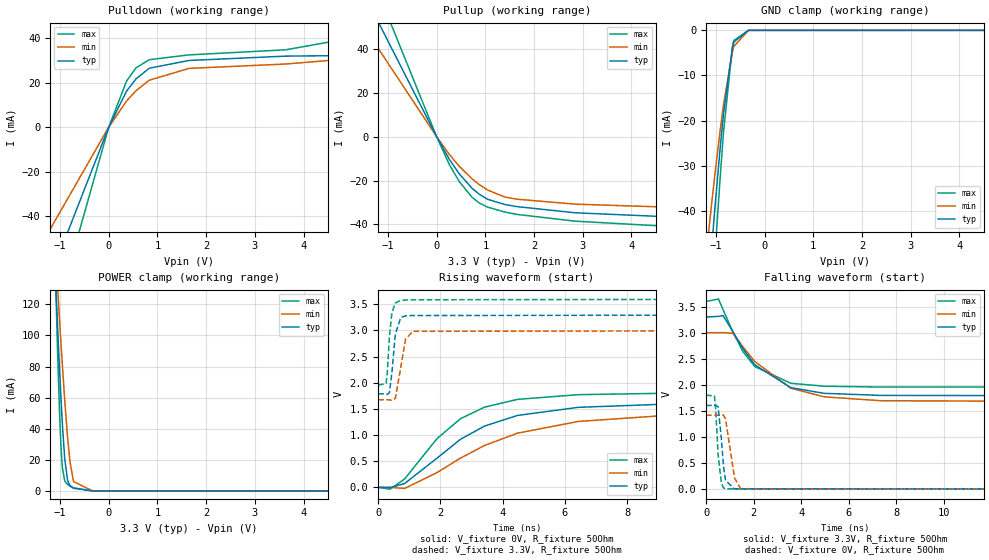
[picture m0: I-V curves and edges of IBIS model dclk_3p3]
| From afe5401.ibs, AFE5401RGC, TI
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|   dclk_3p3 Model
[Model]   dclk_3p3
Model_type   3-state
Polarity   Non-Inverting
Vmeas = 0.9
Vref = 0
Cref = 5pF
Rref = 50
|   typ   min   max
|   (nom PVT)   (fast PVT)   (slow PVT)
C_comp   1.569e-12   1.501e-12   1.667e-12
| Where nom  PVT is Nominal Process, 3.3V, 27C
|   Fast PVT is Strong Process,  3.6V, -40C
|   Slow PVT is Weak Process,   3V, 125C
[Voltage Range]   3.3   3   3.6
|Junction Temperature
[Temperature Range]   27   125   -40
[Pullup Reference]   3.3   3   3.6
[Pulldown Reference]   0   0   0
[Power Clamp Reference]   3.3   3   3.6
[GND Clamp Reference]   0   0   0
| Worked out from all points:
|   slope of the pulldown table from 0 to 0.495 V, typ, clamps not added: 24.7 ohm
|   slope of the pullup table from 0 to 0.495 V, typ, clamps not added: 27.8 ohm
|   POWER clamp passes 1 mA (typ) near -0.65 V on its own axis
|   falling waveform, V_fixture 3.3V, R_fixture 50Ohm: 20-80 % time 1.66ns typ, 2ns min, 1.33ns max; typ from 3.3 V to 1.79 V
|   rising waveform, V_fixture 0V, R_fixture 50Ohm: 20-80 % time 2.46ns typ, 3.24ns min, 1.9ns max; typ from 0 V to 1.61 V
|   rising waveform, V_fixture 3.3V, R_fixture 50Ohm: 20-80 % time 142ps typ, 190ps min, 119ps max; typ from 1.79 V to 3.3 V
|   falling waveform, V_fixture 0V, R_fixture 50Ohm: 20-80 % time 173ps typ, 252ps min, 142ps max; typ from 1.6 V to 0 V
[Pulldown]
|   Voltage   I(typ)   I(min)   I(max)
-3.3V     -185.1mA   -126.1mA   -255.8mA
-3mV      -168.3uA   -114.7uA   -232.5uA
366mV     16.2mA     11.79mA    20.74mA
559.2mV   21.7mA     16.37mA    26.67mA
831mV     26.51mA    21.11mA    30.36mA
1.647V    30.01mA    26.44mA    32.52mA
3.633V    31.97mA    28.41mA    34.81mA
4.498V    32.14mA    29.97mA    38.19mA
5.29V     38.25mA    31.39mA    45.32mA
5.974V    50.12mA    38.95mA    61.62mA
6.29V     58.46mA    44.57mA    72.71mA
6.6V      68.7mA     51.68mA    86.06mA
[GND Clamp]
|   Voltage   I(typ)   I(min)   I(max)
-3.3V     -1.237A    -1.056A    -1.383A
-1.185V   -62.02mA   -48.47mA   -79.23mA
-1.09V    -48.68mA   -38.74mA   -62.09mA
-1.016V   -38.95mA   -31.63mA   -49.47mA
-914.1mV  -26.39mA   -22.38mA   -33mA
-840mV    -18.26mA   -16.29mA   -22.27mA
-660mV    -3.853mA   -4.762mA   -3.675mA
-632.4mV  -2.604mA   -3.574mA   -2.256mA
-330mV    -1.092uA   -13.07uA   -101.3nA
6.6V      0A         0A         0A
[Pullup]
|   Voltage   I(typ)   I(min)   I(max)
-3.3V     144.2mA    111mA      181.3mA
-3mV      131.1uA    100.9uA    164.8uA
260.7mV   -10.34mA   -8.102mA   -12.74mA
462mV     -16.88mA   -13.44mA   -20.42mA
724.8mV   -23.49mA   -19.2mA    -27.59mA
867.9mV   -26.16mA   -21.75mA   -30.15mA
1.046V    -28.58mA   -24.34mA   -32.15mA
1.398V    -30.95mA   -27.54mA   -34.39mA
1.647V    -31.91mA   -28.52mA   -35.47mA
2.835V    -34.73mA   -30.79mA   -38.55mA
5.098V    -36.9mA    -32.42mA   -41.37mA
6.6V      -36.9mA    -32.42mA   -41.37mA
[POWER Clamp]
|   Voltage   I(typ)   I(min)   I(max)
-3.3V     1.983A     1.478A     3.214A
-1.104V   145.1mA    160.1mA    151.1mA
-1.05V    106mA      131.1mA    89.67mA
-1.011V   79.26mA    110.8mA    51.45mA
-981.6mV  60.43mA    95.82mA    29.08mA
-952.8mV  43.58mA    81.6mA     15.12mA
-903mV    20.44mA    58.35mA    6.4mA
-844.8mV  6.804mA    34.5mA     4.15mA
-795mV    3.286mA    18.71mA    3.138mA
-722.7mV  1.758mA    6.011mA    1.936mA
-330mV    1.653uA    10.95uA    250.4nA
6.6V      0A         0A         0A
[Ramp]
R_load = 50
|   typ   min   max
dV/dt_r   0.963548/2.46041e-09   0.850093/3.23116e-09   1.08189/1.89597e-09
dV/dt_f   0.907194/1.66269e-09   0.795985/2.00325e-09   0.987243/1.32794e-09
[Falling Waveform]
V_fixture = 3.3V
V_fixture_min = 3V
V_fixture_max = 3.6V
R_fixture = 50Ohm
|   Time   V(typ)   V(min)   V(max)
0s        3.3V       3V         3.6V
520ps     3.313V     3V         3.645V
715ps     3.328V     3.001V     3.442V
1.13ns    3.017V     2.987V     3.01V
1.55ns    2.694V     2.728V     2.636V
2.05ns    2.383V     2.446V     2.349V
3.565ns   1.945V     1.934V     2.029V
4.975ns   1.836V     1.769V     1.973V
7.34ns    1.797V     1.695V     1.957V
20ns      1.788V     1.673V     1.955V
[Rising Waveform]
V_fixture = 0V
V_fixture_min = 0V
V_fixture_max = 0V
R_fixture = 50Ohm
|   Time   V(typ)   V(min)   V(max)
0s        1.164nV    56.23nV    608.7pV
380ps     -6.246mV   479.9uV    -34.63mV
850ps     73.39mV    -21.18mV   160.8mV
1.89ns    558.7mV    282.7mV    932.3mV
2.645ns   919.5mV    558.6mV    1.313V
3.415ns   1.171V     800.4mV    1.533V
4.475ns   1.375V     1.036V     1.682V
6.43ns    1.53V      1.26V      1.772V
9.02ns    1.586V     1.366V     1.797V
20ns      1.606V     1.417V     1.803V
[Rising Waveform]
V_fixture = 3.3V
V_fixture_min = 3V
V_fixture_max = 3.6V
R_fixture = 50Ohm
|   Time   V(typ)   V(min)   V(max)
0s        1.789V     1.675V     1.955V
255ps     1.786V     1.676V     1.986V
295ps     1.777V     1.675V     2.211V
360ps     1.813V     1.673V     2.882V
440ps     2.188V     1.666V     3.339V
550ps     2.93V      1.701V     3.525V
725ps     3.247V     2.29V      3.575V
880ps     3.279V     2.834V     3.581V
1.115ns   3.285V     2.983V     3.587V
20ns      3.3V       3V         3.6V
[Falling Waveform]
V_fixture = 0V
V_fixture_min = 0V
V_fixture_max = 0V
R_fixture = 50Ohm
|   Time   V(typ)   V(min)   V(max)
0s        1.604V     1.416V     1.801V
350ps     1.605V     1.416V     1.787V
405ps     1.613V     1.416V     1.523V
505ps     1.577V     1.416V     660.2mV
640ps     973.7mV    1.425V     118.4mV
730ps     447.7mV    1.419V     24.88mV
815ps     168.3mV    1.35V      2.83mV
1.195ns   628.2uV    215.1mV    3.469mV
1.46ns    3.623mV    -2.207mV   2.291mV
20ns      -139.1nV   150.8nV    -124.2nV
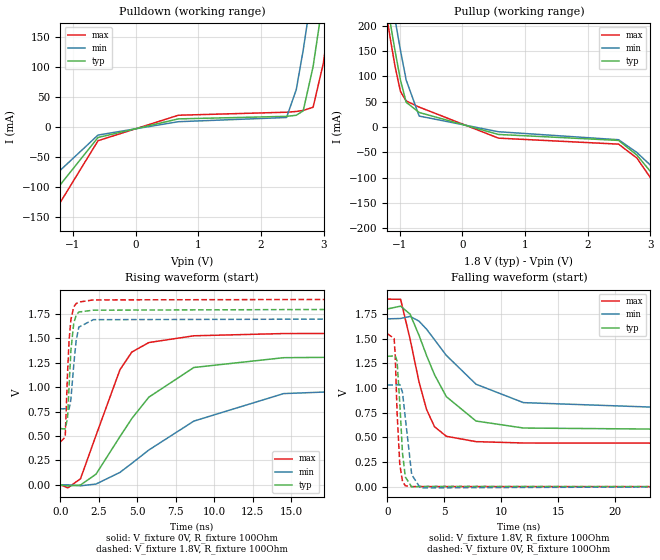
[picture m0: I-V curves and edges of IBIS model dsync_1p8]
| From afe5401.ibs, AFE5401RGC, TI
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|   dsync_1p8 Model
[Model]   dsync_1p8
Model_type   Output
Polarity   Non-Inverting
Vmeas = 0.9
Vref = 0
Cref = 5pF
Rref = 100
|   typ   min   max
|   (nom PVT)   (fast PVT)   (slow PVT)
C_comp   1.711e-12   1.676e-12   1.765e-12
| Where nom  PVT is Nominal Process, 1.8V, 27C
|   Fast PVT is Strong Process,  1.9V, -40C
|   Slow PVT is Weak Process,   1.7V, 125C
[Voltage Range]   1.8   1.7   1.9
|Junction Temperature
[Temperature Range]   27   125   -40
[Pullup Reference]   1.8   1.7   1.9
[Pulldown Reference]   0   0   0
[Power Clamp Reference]   1.8   1.7   1.9
[GND Clamp Reference]   0   0   0
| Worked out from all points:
|   slope of the pulldown table from 0 to 0.27 V, typ, clamps not added: 39.5 ohm
|   slope of the pullup table from 0 to 0.27 V, typ, clamps not added: 31.9 ohm
|   falling waveform, V_fixture 1.8V, R_fixture 100Ohm: 20-80 % time 3.06ns typ, 4.95ns min, 1.79ns max; typ from 1.8 V to 0.577 V
|   rising waveform, V_fixture 0V, R_fixture 100Ohm: 20-80 % time 3.86ns typ, 6.76ns min, 2.16ns max; typ from 0 V to 1.32 V
|   rising waveform, V_fixture 1.8V, R_fixture 100Ohm: 20-80 % time 267ps typ, 325ps min, 246ps max; typ from 0.577 V to 1.8 V
|   falling waveform, V_fixture 0V, R_fixture 100Ohm: 20-80 % time 384ps typ, 543ps min, 312ps max; typ from 1.32 V to 0 V
[Pulldown]
|   Voltage   I(typ)   I(min)   I(max)
-1.8V     -236.1mA   -155mA     -317.1mA
-1.639V   -163.8mA   -117.4mA   -227.2mA
-1.545V   -141.3mA   -105.7mA   -184.4mA
-599.8mV  -17.59mA   -13.54mA   -22.97mA
682mV     13.43mA    8.736mA    19.52mA
2.409V    17.67mA    15.77mA    24.59mA
2.564V    19.46mA    62.19mA    25.8mA
2.675V    26.87mA    128.2mA    27.54mA
2.833V    100.7mA    238.4mA    32.82mA
2.996V    215.2mA    358.9mA    106.1mA
3.201V    372.2mA    516.7mA    258.6mA
3.6V      687mA      828.7mA    575.7mA
[Pullup]
|   Voltage   I(typ)   I(min)   I(max)
-1.8V     721.1mA    774.9mA    698.7mA
-1.186V   231.1mA    293.4mA    200mA
-1.142V   197.9mA    260.3mA    166.6mA
-1.076V   149.8mA    211.9mA    119.3mA
-990.8mV  92.93mA    151.7mA    70.16mA
-899.4mV  48.82mA    92.82mA    51.41mA
-691.6mV  28.54mA    21.5mA     39.21mA
574.2mV   -14.85mA   -9.506mA   -22.14mA
2.491V    -26.62mA   -25.29mA   -33.98mA
2.783V    -55.48mA   -50.45mA   -61.4mA
3.402V    -148.6mA   -122mA     -172.3mA
3.6V      -230.9mA   -188.8mA   -260.5mA
[Ramp]
R_load = 100
|   typ   min   max
dV/dt_r   0.792675/3.84787e-09   0.615366/6.74933e-09   0.930156/2.15375e-09
dV/dt_f   0.7338/3.05246e-09   0.552843/4.92497e-09   0.875843/1.78863e-09
[Falling Waveform]
V_fixture = 1.8V
V_fixture_min = 1.7V
V_fixture_max = 1.9V
R_fixture = 100Ohm
|   Time   V(typ)   V(min)   V(max)
0s        1.8V       1.7V       1.9V
1.165ns   1.829V     1.704V     1.898V
1.995ns   1.748V     1.725V     1.496V
2.78ns    1.533V     1.677V     1.061V
3.445ns   1.328V     1.595V     781mV
4.14ns    1.134V     1.489V     606.7mV
5.175ns   911.9mV    1.33V      510.6mV
7.78ns    665mV      1.038V     456.2mV
11.94ns   594.1mV    851.4mV    442.3mV
30ns      577mV      778.6mV    440.3mV
[Rising Waveform]
V_fixture = 0V
V_fixture_min = 0V
V_fixture_max = 0V
R_fixture = 100Ohm
|   Time   V(typ)   V(min)   V(max)
0s        1.498nV    92.24nV    718.7pV
485ps     -10.86mV   798.6uV    -30.09mV
1.305ns   -919.9uV   -9.116mV   63.24mV
2.315ns   110.1mV    8.952mV    506.8mV
3.87ns    493.7mV    128mV      1.177V
4.645ns   679.1mV    220.7mV    1.359V
5.75ns    897.3mV    356.9mV    1.456V
8.68ns    1.201V     652.7mV    1.525V
14.52ns   1.301V     933.9mV    1.548V
30ns      1.321V     1.026V     1.55V
[Rising Waveform]
V_fixture = 1.8V
V_fixture_min = 1.7V
V_fixture_max = 1.9V
R_fixture = 100Ohm
|   Time   V(typ)   V(min)   V(max)
0s        577mV      778mV      440.3mV
310ps     571.1mV    779.3mV    488.8mV
460ps     682.7mV    768mV      1.137V
560ps     1.002V     774.8mV    1.474V
680ps     1.375V     873.9mV    1.69V
865ps     1.652V     1.227V     1.819V
1.02ns    1.734V     1.474V     1.855V
1.195ns   1.768V     1.614V     1.87V
2.14ns    1.787V     1.69V      1.892V
30ns      1.8V       1.7V       1.9V
[Falling Waveform]
V_fixture = 0V
V_fixture_min = 0V
V_fixture_max = 0V
R_fixture = 100Ohm
|   Time   V(typ)   V(min)   V(max)
0s        1.321V     1.03V      1.55V
600ps     1.324V     1.03V      1.502V
700ps     1.325V     1.03V      1.31V
855ps     1.274V     1.032V     752.6mV
1.095ns   842.2mV    1.034V     224.2mV
1.33ns    342.3mV    956.7mV    55.76mV
1.575ns   98.99mV    699.5mV    9.004mV
2.14ns    -3.179mV   121.8mV    1.184mV
2.885ns   2.763mV    -12.14mV   1.088mV
30ns      17.74nV    451.4nV    -6.784pV
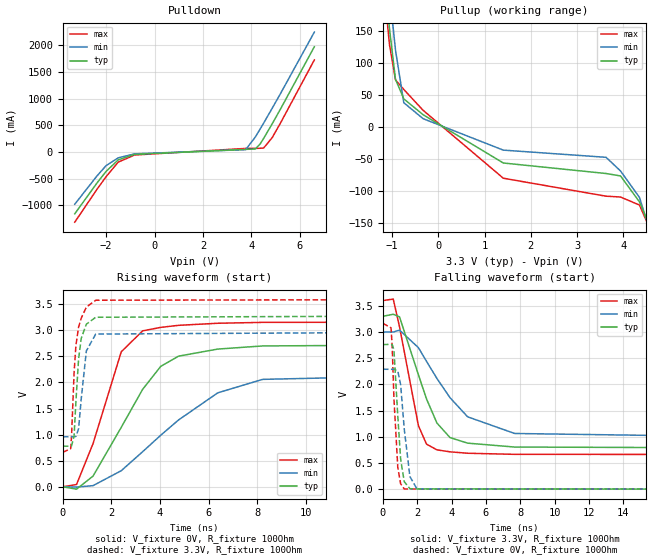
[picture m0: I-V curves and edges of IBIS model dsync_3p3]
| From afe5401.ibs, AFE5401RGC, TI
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|   dsync_3p3 Model
[Model]   dsync_3p3
Model_type   Output
Polarity   Non-Inverting
Vmeas = 1.65
Vref = 0
Cref = 5pF
Rref = 50
|   typ   min   max
|   (nom PVT)   (fast PVT)   (slow PVT)
C_comp   1.702e-12   1.650e-12   1.756e-12
| Where nom  PVT is Nominal Process, 3.3V, 27C
|   Fast PVT is Strong Process,  3.6V, -40C
|   Slow PVT is Weak Process,   3V, 125C
[Voltage Range]   3.3   3   3.6
|Junction Temperature
[Temperature Range]   27   125   -40
[Pullup Reference]   3.3   3   3.6
[Pulldown Reference]   0   0   0
[Power Clamp Reference]   3.3   3   3.6
[GND Clamp Reference]   0   0   0
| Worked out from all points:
|   slope of the pulldown table from 0 to 0.495 V, typ, clamps not added: 29.3 ohm
|   slope of the pullup table from 0 to 0.495 V, typ, clamps not added: 19.3 ohm
|   falling waveform, V_fixture 3.3V, R_fixture 100Ohm: 20-80 % time 1.62ns typ, 2.72ns min, 1.02ns max; typ from 3.3 V to 0.779 V
|   rising waveform, V_fixture 0V, R_fixture 100Ohm: 20-80 % time 2.07ns typ, 3.73ns min, 1.24ns max; typ from 0 V to 2.76 V
|   rising waveform, V_fixture 3.3V, R_fixture 100Ohm: 20-80 % time 236ps typ, 257ps min, 244ps max; typ from 0.779 V to 3.3 V
|   falling waveform, V_fixture 0V, R_fixture 100Ohm: 20-80 % time 290ps typ, 375ps min, 245ps max; typ from 2.76 V to 0 V
[Pulldown]
|   Voltage   I(typ)   I(min)   I(max)
-3.3V     -1.156A    -976.6mA   -1.313A
-2.383V   -580.4mA   -448.3mA   -698.2mA
-2.004V   -361.6mA   -254mA     -460.9mA
-1.505V   -146.8mA   -109.2mA   -189mA
-826.8mV  -43.44mA   -33.77mA   -55.52mA
3.762V    49.64mA    45.52mA    67.55mA
4.163V    57.73mA    282mA      68.34mA
4.354V    147.1mA    425.1mA    70.8mA
4.503V    253.7mA    540.2mA    74.5mA
4.858V    528.6mA    819.2mA    269.4mA
5.188V    793.9mA    1.083A     532.1mA
6.6V      1.971A     2.245A     1.724A
[Pullup]
|   Voltage   I(typ)   I(min)   I(max)
-3.3V     2.002A     2.025A     2.009A
-1.233V   287.1mA    343.1mA    261.9mA
-1.057V   154.4mA    210.9mA    129.3mA
-927.3mV  75.21mA    121.2mA    74.17mA
-747mV    44.27mA    38.29mA    59.03mA
-330mV    19.48mA    13.28mA    26.43mA
1.405V    -56.19mA   -36.01mA   -80.04mA
3.627V    -72.67mA   -47.28mA   -108.2mA
3.94V     -76.46mA   -68.68mA   -109.5mA
4.35V     -117.1mA   -110.1mA   -122.1mA
4.97V     -224.5mA   -254.7mA   -224.5mA
6.6V      -1.231A    -1.202A    -1.216A
[Ramp]
R_load = 100
|   typ   min   max
dV/dt_r   1.65605/2.07194e-09   1.37204/3.71277e-09   1.89978/1.23326e-09
dV/dt_f   1.51265/1.61552e-09   1.22443/2.7146e-09   1.7642/1.02101e-09
[Falling Waveform]
V_fixture = 3.3V
V_fixture_min = 3V
V_fixture_max = 3.6V
R_fixture = 100Ohm
|   Time   V(typ)   V(min)   V(max)
0s        3.3V       3V         3.6V
605ps     3.339V     2.999V     3.629V
970ps     3.289V     3.036V     3.1V
2.07ns    2.184V     2.701V     1.211V
2.54ns    1.724V     2.442V     860.3mV
3.145ns   1.263V     2.114V     750.4mV
3.91ns    984.5mV    1.746V     712.8mV
4.935ns   878.5mV    1.381V     685.8mV
7.67ns    804.2mV    1.063V     664.8mV
30ns      778.9mV    959.3mV    659.7mV
[Rising Waveform]
V_fixture = 0V
V_fixture_min = 0V
V_fixture_max = 0V
R_fixture = 100Ohm
|   Time   V(typ)   V(min)   V(max)
0s        2.089nV    93.15nV    1.157nV
565ps     -45.5mV    -5.412mV   43.54mV
1.245ns   204.9mV    22.16mV    827.5mV
2.405ns   1.14V      308.4mV    2.589V
3.285ns   1.869V     672.7mV    2.99V
4.03ns    2.31V      989mV      3.057V
4.76ns    2.505V     1.281V     3.096V
6.375ns   2.641V     1.802V     3.136V
8.22ns    2.701V     2.06V      3.153V
30ns      2.76V      2.287V     3.166V
[Rising Waveform]
V_fixture = 3.3V
V_fixture_min = 3V
V_fixture_max = 3.6V
R_fixture = 100Ohm
|   Time   V(typ)   V(min)   V(max)
0s        778.9mV    959.2mV    659.7mV
325ps     779.1mV    959.5mV    731.1mV
360ps     782.6mV    959.2mV    963.8mV
465ps     977.3mV    957.8mV    2.183V
540ps     1.631V     967mV      2.712V
650ps     2.451V     1.113V     3.063V
760ps     2.848V     1.691V     3.234V
970ps     3.118V     2.606V     3.446V
1.355ns   3.251V     2.929V     3.578V
30ns      3.3V       3V         3.6V
[Falling Waveform]
V_fixture = 0V
V_fixture_min = 0V
V_fixture_max = 0V
R_fixture = 100Ohm
|   Time   V(typ)   V(min)   V(max)
0s        2.76V      2.289V     3.166V
475ps     2.765V     2.288V     3.081V
545ps     2.76V      2.288V     2.718V
645ps     2.659V     2.29V      1.731V
870ps     1.391V     2.256V     413.6mV
1.035ns   574.4mV    1.997V     102.1mV
1.245ns   143.1mV    1.15V      3.878mV
1.575ns   8.896mV    240mV      4.864mV
1.985ns   4.939mV    5.286mV    3.701mV
30ns      21.9nV     293.6nV    295.9pV
